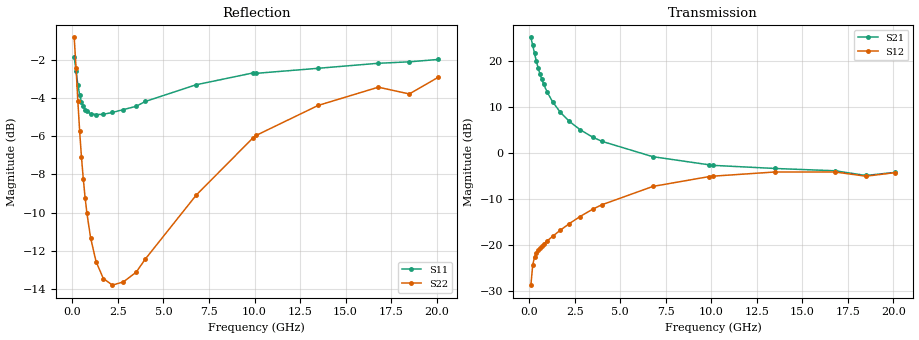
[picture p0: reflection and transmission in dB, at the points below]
!  Infineon Technologies AG
! BFR380L3 , PF131585-7, No.6, Th 09.10.01, soldered on pcb-board, measured with PP GSG850
!  Vce=0.75 V,  Ic=6.0 mA
! Common Emitter S-Parameters:  15. November 2001
#  GHz  S  MA  R  50
! f  S11  S21  S12  S22
! GHz  Mag  Ang  Mag  Ang  Mag  Ang  Mag  Ang
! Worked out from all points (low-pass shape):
!   201 points, 100 MHz to 20.1 GHz, reference 50 ohm
!   highest |S21| = 25.21 dB at 100 MHz (marker M1); lowest = -4.9 dB at 18.5 GHz (marker M2)
!   |S21| within 3 dB of the highest: start of sweep to 273.6 MHz
!   lowest |S11| = -4.9 dB at 1.3 GHz (marker M3), VSWR 3.66, Z = 13.7 - j3.15 ohm
!   |S11| at or under -10 dB: nowhere
!   |S22| runs from -13.8 to -0.8 dB; largest |S21 - S12| = 18
!   S11 on the Smith chart (normalised r, x): 100 MHz: 0.85, -2.54; 300 MHz: 0.34, -0.86; 1 GHz: 0.28, -0.16; 4 GHz: 0.27, +0.38; 9.9 GHz: 0.37, +1.16; 20.1 GHz: 0.96, +2.58
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0.1  0.8091 -39.5  18.22 155.4  0.03647 69.8  0.9093 -26.4
0.2  0.742 -71.2  15.02 136.6  0.06 56.0  0.758 -46.8
0.3  0.6835 -95.1  12.21 123.6  0.07404 48.1  0.6196 -61.3
0.4  0.6429 -112.4  10.06 114.3  0.08238 43.6  0.516 -72.0
0.5  0.6163 -125.3  8.464 107.4  0.08866 41.5  0.4413 -80.3
0.6  0.601 -135.3  7.265 102.1  0.09351 40.7  0.387 -87.0
0.7  0.5886 -143.5  6.361 97.6  0.09815 40.3  0.3458 -92.7
0.8  0.5821 -150.1  5.637 93.9  0.1024 40.6  0.3147 -97.7
1  0.5744 -160.5  4.602 87.6  0.1109 41.6  0.2719 -106.1
1.3  0.571 -172.2  3.606 80.0  0.1242 43.7  0.2355 -116.6
1.7  0.5721 176.4  2.811 71.6  0.1438 46.1  0.2127 -127.7
2.2  0.5785 165.1  2.227 62.5  0.1701 47.7  0.2044 -138.7
2.8  0.5885 154.0  1.801 53.0  0.2036 48.1  0.2084 -149.8
3.5  0.6002 142.5  1.489 43.0  0.2453 47.0  0.2209 -159.9
4  0.618 135.6  1.343 36.9  0.2737 45.5  0.239 -167.8
6.8  0.6836 102.7  0.9139 9.8  0.4336 30.3  0.3516 156.2
9.9  0.7337 78.0  0.7449 -7.7  0.5555 10.3  0.4954 125.1
10.1  0.7323 76.6  0.7353 -8.7  0.5608 9.0  0.5041 123.2
13.5  0.7548 59.1  0.6802 -22.8  0.6228 -11.7  0.6036 95.3
16.8  0.7779 47.3  0.642 -33.9  0.6228 -27.2  0.6736 74.6
18.5  0.7848 45.3  0.5703 -41.1  0.5601 -35.6  0.6467 69.3
20.1  0.7963 38.1  0.6169 -44.7  0.6131 -40.4  0.7156 58.9
